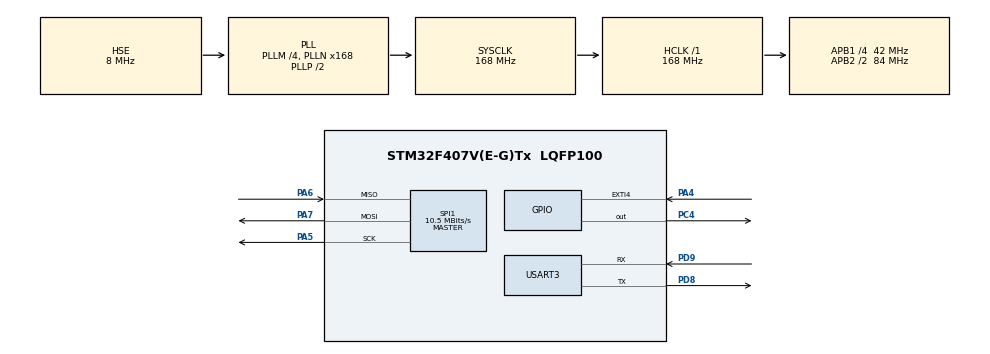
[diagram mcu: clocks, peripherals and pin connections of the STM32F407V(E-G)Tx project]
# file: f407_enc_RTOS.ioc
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Mcu.Family=STM32F4
RCC.PLLSourceVirtual=RCC_PLLSOURCE_HSE
NVIC.EXTI4_IRQn=true\:5\:0\:false\:false\:true\:true\:true\:true
PA6.Mode=Full_Duplex_Master
PH0-OSC_IN.Signal=RCC_OSC_IN
RCC.CortexFreq_Value=168000000
FREERTOS.Tasks01=defaultTask,0,128,StartDefaultTask,Default,NULL,Dynamic,NULL,NULL;Tcp,-3,128,Tcp_fn,Default,NULL,Dynamic,NULL,NULL
PA7.Mode=Full_Duplex_Master
SPI1.VirtualType=VM_MASTER
PC4.Signal=GPIO_Output
PD9.Signal=USART3_RX
RCC.APB1CLKDivider=RCC_HCLK_DIV4
PD9.Mode=Asynchronous
RCC.SYSCLKSource=RCC_SYSCLKSOURCE_PLLCLK
ProjectManager.StackSize=0x400
ProjectManager.TargetToolchain=TrueSTUDIO
SPI1.Direction=SPI_DIRECTION_2LINES
RCC.HCLKFreq_Value=168000000
RCC.APB2TimFreq_Value=168000000
TIM3.Period=999
SPI1.CalculateBaudRate=10.5 MBits/s
PD8.Signal=USART3_TX
TIM4.Prescaler=83
PD8.Mode=Asynchronous
RCC.AHBFreq_Value=168000000
PH0-OSC_IN.Mode=HSE-External-Oscillator
PA5.Signal=SPI1_SCK
RCC.HSE_VALUE=8000000
board=custom
RCC.VCOOutputFreq_Value=336000000
NVIC.TIM3_IRQn=true\:5\:0\:false\:false\:true\:true\:true\:true
RCC.APB2Freq_Value=84000000
SPI1.Mode=SPI_MODE_MASTER
TIM3.Prescaler=83
NVIC.TIM2_IRQn=true\:0\:0\:false\:false\:true\:false\:false\:true
PH1-OSC_OUT.Signal=RCC_OSC_OUT
TIM4.Period=999
VP_FREERTOS_VS_CMSIS_V1.Mode=CMSIS_V1
Mcu.Name=STM32F407V(E-G)Tx
FREERTOS.configTOTAL_HEAP_SIZE=51200
PH1-OSC_OUT.Mode=HSE-External-Oscillator
RCC.48MHZClocksFreq_Value=84000000
PA4.Signal=GPXTI4
RCC.SYSCLKFreq_VALUE=168000000
Mcu.Package=LQFP100
VP_SYS_VS_tim2.Mode=TIM2
PA6.Signal=SPI1_MISO
NVIC.TimeBase=TIM2_IRQn
USART3.VirtualMode=VM_ASYNC
NVIC.TimeBaseIP=TIM2
ProjectManager.HeapSize=0x200
RCC.HSI_VALUE=16000000
VP_TIM4_VS_ClockSourceINT.Mode=Internal
NVIC.PriorityGroup=NVIC_PRIORITYGROUP_4
RCC.APB2CLKDivider=RCC_HCLK_DIV2
RCC.PLLM=4
RCC.PLLN=168
RCC.APB1TimFreq_Value=84000000
NVIC.TIM4_IRQn=true\:5\:0\:false\:false\:true\:true\:true\:true
RCC.APB1Freq_Value=42000000
SPI1.BaudRatePrescaler=SPI_BAUDRATEPRESCALER_8
VP_TIM3_VS_ClockSourceINT.Mode=Internal
PA5.Mode=Full_Duplex_Master
PA7.Signal=SPI1_MOSI

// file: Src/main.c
/* USER CODE BEGIN Header */
/**
  ******************************************************************************
  * @file           : main.c
  * @brief          : Main program body
  ******************************************************************************
  * @attention
  *
  * <h2><center>&copy; Copyright (c) 2020 STMicroelectronics.
  * All rights reserved.</center></h2>
  *
  * This software component is licensed by ST under Ultimate Liberty license
  * SLA0044, the "License"; You may not use this file except in compliance with
  * the License. You may obtain a copy of the License at:
  *                             www.st.com/SLA0044
  *
  ******************************************************************************
  */
/* USER CODE END Header */

#include "main.h"
#include "cmsis_os.h"

/* USER CODE BEGIN Includes */
#include "lwip.h"
#include "ethernetif.h"
#include "app_ethernet.h"
#include "lwip/netif.h"
#include "lwip/tcpip.h"
#include "lwip/timeouts.h"
#include "lwip_mqtt.h"
#include "dht_22.h"

/* USER CODE END Includes */

SPI_HandleTypeDef hspi1;

TIM_HandleTypeDef htim3;
TIM_HandleTypeDef htim4;

UART_HandleTypeDef huart3;

osThreadId defaultTaskHandle;
osThreadId TcpHandle;
/* USER CODE BEGIN PV */
uint8_t Rh_byte1, Rh_byte2, Temp_byte1, Temp_byte2;
uint16_t sum, RH, TEMP;
int temp_low=0, temp_high=0, rh_low=0, rh_high=0;
GPIO_InitTypeDef GPIO_InitStruct;
/* USER CODE END PV */

void SystemClock_Config(void);
static void MX_GPIO_Init(void);
static void MX_SPI1_Init(void);
static void MX_TIM3_Init(void);
static void MX_TIM4_Init(void);
static void MX_USART3_UART_Init(void);
void StartDefaultTask(void const * argument);
void Tcp_fn(void const * argument);

/* USER CODE BEGIN PFP */
ip4_addr_t ipaddr;
ip4_addr_t netmask;
ip4_addr_t gw;
uint8_t IP_ADDRESS[4];
uint8_t NETMASK_ADDRESS[4];
uint8_t GATEWAY_ADDRESS[4];

/* USER CODE BEGIN 2 */
 struct netif gnetif; /* network interface structure */
 char pacote[1000];
 mqtt_client_t *client;
 uint32_t counter,tiner=0;
 struct netif gnetif; /* network interface structure */
 /* Semaphore to signal Ethernet Link state update */
 osSemaphoreId Netif_IRQSemaphore = NULL;
 /* Ethernet link thread Argument */
 struct enc_irq_str irq_arg;
/* USER CODE END PFP */

/* USER CODE BEGIN 0 */
 void MX_LWIP_Init(void);

#if (defined(__GNUC__) && !defined(__CC_ARM))
/* With GCC/RAISONANCE, small printf (option LD Linker->Libraries->Small printf
   set to 'Yes') calls __io_putchar() */
#define PUTCHAR_PROTOTYPE int __io_putchar(int ch)
#define GETCHAR_PROTOTYPE int __io_getchar(void)
#else
#define PUTCHAR_PROTOTYPE int fputc(int ch, FILE *f)
#define GETCHAR_PROTOTYPE int fgetc(FILE *f)
#endif /* __GNUC__ */

/**
  * @brief  Retargets the C library printf function to the USART.
  * @param  None
  * @retval None
  */
PUTCHAR_PROTOTYPE
{
  /* Place your implementation of fputc here */
  /* e.g. write a character to the USART2 and Loop until the end of transmission */
  while (HAL_OK != HAL_UART_Transmit(&huart3, (uint8_t *) &ch, 1, 30000))
  {
    ;
  }
  return ch;
}

/**
  * @brief  Retargets the C library scanf function to the USART.
  * @param  None
  * @retval None
  */
GETCHAR_PROTOTYPE
{
  /* Place your implementation of fgetc here */
  /* e.g. read a character on USART and loop until the end of read */
  uint8_t ch = 0;
  while (HAL_OK != HAL_UART_Receive(&huart3, (uint8_t *)&ch, 1, 30000))
  {
    ;
  }
  return ch;
}
/* USER CODE END 0 */

int main(void)
{

  /* MCU Configuration--------------------------------------------------------*/

  /* Reset of all peripherals, Initializes the Flash interface and the Systick. */
  HAL_Init();

  /* Configure the system clock */
  SystemClock_Config();

  /* Initialize all configured peripherals */
  MX_GPIO_Init();
  MX_SPI1_Init();
  MX_TIM3_Init();
  MX_TIM4_Init();
  MX_USART3_UART_Init();

  /* Create the thread(s) */
  /* definition and creation of defaultTask */

  /* Start scheduler */

  osThreadDef(defaultTask, StartDefaultTask, osPriorityNormal, 0, (9*1024));
  defaultTaskHandle = osThreadCreate(osThread(defaultTask), NULL);

  /* definition and creation of Tcp */
  osThreadDef(Tcp, Tcp_fn, osPriorityIdle, 0, 128);
  TcpHandle = osThreadCreate(osThread(Tcp), NULL);

  /* Start scheduler */
  osKernelStart();

  /* We should never get here as control is now taken by the scheduler */
  /* Infinite loop */
  while (1)
  {

  }
}

void SystemClock_Config(void)
{
  RCC_OscInitTypeDef RCC_OscInitStruct = {0};
  RCC_ClkInitTypeDef RCC_ClkInitStruct = {0};

  /** Configure the main internal regulator output voltage
  */
  __HAL_RCC_PWR_CLK_ENABLE();
  __HAL_PWR_VOLTAGESCALING_CONFIG(PWR_REGULATOR_VOLTAGE_SCALE1);
  /** Initializes the CPU, AHB and APB busses clocks
  */
  RCC_OscInitStruct.OscillatorType = RCC_OSCILLATORTYPE_HSE;
  RCC_OscInitStruct.HSEState = RCC_HSE_ON;
  RCC_OscInitStruct.PLL.PLLState = RCC_PLL_ON;
  RCC_OscInitStruct.PLL.PLLSource = RCC_PLLSOURCE_HSE;
  RCC_OscInitStruct.PLL.PLLM = 4;
  RCC_OscInitStruct.PLL.PLLN = 168;
  RCC_OscInitStruct.PLL.PLLP = RCC_PLLP_DIV2;
  RCC_OscInitStruct.PLL.PLLQ = 4;
  if (HAL_RCC_OscConfig(&RCC_OscInitStruct) != HAL_OK)
  {
    Error_Handler();
  }
  /** Initializes the CPU, AHB and APB busses clocks
  */
  RCC_ClkInitStruct.ClockType = RCC_CLOCKTYPE_HCLK|RCC_CLOCKTYPE_SYSCLK
                              |RCC_CLOCKTYPE_PCLK1|RCC_CLOCKTYPE_PCLK2;
  RCC_ClkInitStruct.SYSCLKSource = RCC_SYSCLKSOURCE_PLLCLK;
  RCC_ClkInitStruct.AHBCLKDivider = RCC_SYSCLK_DIV1;
  RCC_ClkInitStruct.APB1CLKDivider = RCC_HCLK_DIV4;
  RCC_ClkInitStruct.APB2CLKDivider = RCC_HCLK_DIV2;

  if (HAL_RCC_ClockConfig(&RCC_ClkInitStruct, FLASH_LATENCY_5) != HAL_OK)
  {
    Error_Handler();
  }
}

static void MX_SPI1_Init(void)
{

  /* SPI1 parameter configuration*/
  hspi1.Instance = SPI1;
  hspi1.Init.Mode = SPI_MODE_MASTER;
  hspi1.Init.Direction = SPI_DIRECTION_2LINES;
  hspi1.Init.DataSize = SPI_DATASIZE_8BIT;
  hspi1.Init.CLKPolarity = SPI_POLARITY_LOW;
  hspi1.Init.CLKPhase = SPI_PHASE_1EDGE;
  hspi1.Init.NSS = SPI_NSS_SOFT;
  hspi1.Init.BaudRatePrescaler = SPI_BAUDRATEPRESCALER_8;
  hspi1.Init.FirstBit = SPI_FIRSTBIT_MSB;
  hspi1.Init.TIMode = SPI_TIMODE_DISABLE;
  hspi1.Init.CRCCalculation = SPI_CRCCALCULATION_DISABLE;
  hspi1.Init.CRCPolynomial = 10;
  if (HAL_SPI_Init(&hspi1) != HAL_OK)
  {
    Error_Handler();
  }

}

static void MX_TIM3_Init(void)
{

  TIM_ClockConfigTypeDef sClockSourceConfig = {0};
  TIM_MasterConfigTypeDef sMasterConfig = {0};

  htim3.Instance = TIM3;
  htim3.Init.Prescaler = 83;
  htim3.Init.CounterMode = TIM_COUNTERMODE_UP;
  htim3.Init.Period = 999;
  htim3.Init.ClockDivision = TIM_CLOCKDIVISION_DIV1;
  htim3.Init.AutoReloadPreload = TIM_AUTORELOAD_PRELOAD_DISABLE;
  if (HAL_TIM_Base_Init(&htim3) != HAL_OK)
  {
    Error_Handler();
  }
  sClockSourceConfig.ClockSource = TIM_CLOCKSOURCE_INTERNAL;
  if (HAL_TIM_ConfigClockSource(&htim3, &sClockSourceConfig) != HAL_OK)
  {
    Error_Handler();
  }
  sMasterConfig.MasterOutputTrigger = TIM_TRGO_RESET;
  sMasterConfig.MasterSlaveMode = TIM_MASTERSLAVEMODE_DISABLE;
  if (HAL_TIMEx_MasterConfigSynchronization(&htim3, &sMasterConfig) != HAL_OK)
  {
    Error_Handler();
  }

}

static void MX_TIM4_Init(void)
{

  TIM_ClockConfigTypeDef sClockSourceConfig = {0};
  TIM_MasterConfigTypeDef sMasterConfig = {0};

  htim4.Instance = TIM4;
  htim4.Init.Prescaler = 83;
  htim4.Init.CounterMode = TIM_COUNTERMODE_UP;
  htim4.Init.Period = 9;
  htim4.Init.ClockDivision = TIM_CLOCKDIVISION_DIV1;
  htim4.Init.AutoReloadPreload = TIM_AUTORELOAD_PRELOAD_DISABLE;
  if (HAL_TIM_Base_Init(&htim4) != HAL_OK)
  {
    Error_Handler();
  }
  sClockSourceConfig.ClockSource = TIM_CLOCKSOURCE_INTERNAL;
  if (HAL_TIM_ConfigClockSource(&htim4, &sClockSourceConfig) != HAL_OK)
  {
    Error_Handler();
  }
  sMasterConfig.MasterOutputTrigger = TIM_TRGO_RESET;
  sMasterConfig.MasterSlaveMode = TIM_MASTERSLAVEMODE_DISABLE;
  if (HAL_TIMEx_MasterConfigSynchronization(&htim4, &sMasterConfig) != HAL_OK)
  {
    Error_Handler();
  }

}

static void MX_USART3_UART_Init(void)
{

  huart3.Instance = USART3;
  huart3.Init.BaudRate = 115200;
  huart3.Init.WordLength = UART_WORDLENGTH_8B;
  huart3.Init.StopBits = UART_STOPBITS_1;
  huart3.Init.Parity = UART_PARITY_NONE;
  huart3.Init.Mode = UART_MODE_TX_RX;
  huart3.Init.HwFlowCtl = UART_HWCONTROL_NONE;
  huart3.Init.OverSampling = UART_OVERSAMPLING_16;
  if (HAL_UART_Init(&huart3) != HAL_OK)
  {
    Error_Handler();
  }

}

static void MX_GPIO_Init(void)
{
  GPIO_InitTypeDef GPIO_InitStruct = {0};

  /* GPIO Ports Clock Enable */
  __HAL_RCC_GPIOH_CLK_ENABLE();
  __HAL_RCC_GPIOA_CLK_ENABLE();
  __HAL_RCC_GPIOC_CLK_ENABLE();
  __HAL_RCC_GPIOD_CLK_ENABLE();

  /*Configure GPIO pin Output Level */
  HAL_GPIO_WritePin(GPIOC, GPIO_PIN_4, GPIO_PIN_RESET);

  /*Configure GPIO pin : PA4 */
  GPIO_InitStruct.Pin = GPIO_PIN_4;
  GPIO_InitStruct.Mode = GPIO_MODE_IT_RISING;
  GPIO_InitStruct.Pull = GPIO_NOPULL;
  HAL_GPIO_Init(GPIOA, &GPIO_InitStruct);

  /*Configure GPIO pin : PC4 */
  GPIO_InitStruct.Pin = GPIO_PIN_4;
  GPIO_InitStruct.Mode = GPIO_MODE_OUTPUT_PP;
  GPIO_InitStruct.Pull = GPIO_NOPULL;
  GPIO_InitStruct.Speed = GPIO_SPEED_FREQ_LOW;
  HAL_GPIO_Init(GPIOC, &GPIO_InitStruct);

  HAL_GPIO_WritePin(GPIOC, DHT_22_PWR_Pin|DHT_22_GND_Pin, GPIO_PIN_RESET);
  /*Configure GPIO pins : DHT_22_PWR_Pin DHT_22_GND_Pin */
  GPIO_InitStruct.Pin = DHT_22_PWR_Pin|DHT_22_GND_Pin;
  GPIO_InitStruct.Mode = GPIO_MODE_OUTPUT_PP;
  GPIO_InitStruct.Pull = GPIO_NOPULL;
  GPIO_InitStruct.Speed = GPIO_SPEED_FREQ_LOW;
  HAL_GPIO_Init(GPIOC, &GPIO_InitStruct);

  /*Configure GPIO pin : DHT_22_IN_OUT_Pin */
  GPIO_InitStruct.Pin = DHT_22_IN_OUT_Pin;
  GPIO_InitStruct.Mode = GPIO_MODE_INPUT;
  GPIO_InitStruct.Pull = GPIO_NOPULL;
  HAL_GPIO_Init(DHT_22_IN_OUT_GPIO_Port, &GPIO_InitStruct);

  /* EXTI interrupt init*/
  HAL_NVIC_SetPriority(EXTI4_IRQn, 5, 0);
  HAL_NVIC_EnableIRQ(EXTI4_IRQn);

}

void StartDefaultTask(void const * argument)
{
  /* USER CODE BEGIN 5 */
	  MX_LWIP_Init();
	  User_notification(&gnetif);
	  client = mqtt_client_new();
	 if(client != NULL) {
	    sprintf(pacote,"hello_mohamed");
	     example_do_connect(client, "hello_world");
	     example_publish(client, pacote);
	 }
	   if(HAL_TIM_Base_Init(&htim3) != HAL_OK)
	   {
	     /* Initialization Error */
	     Error_Handler();
	   }

	   /*##-2- Start the TIM Base generation in interrupt mode ####################*/
	   /* Start Channel1 */
	   if(HAL_TIM_Base_Start_IT(&htim3) != HAL_OK)
	   {
	     /* Starting Error */
	     Error_Handler();
	   }
  /* Infinite loop */
  for(;;)
  {
ethernetif_input(&gnetif);
  /* Triggers actual ethernet transmission if transmission buffers are not empty */
 ethernet_transmit();
 osDelay(1);
 if(counter>399){
	   counter =0;
if(client != NULL) {
 tiner++;
 example_do_connect(client, "hello_world");
 sprintf(pacote,"hell timer:%d",tiner);
 example_publish(client, pacote);
  }
 }

  /* Handle timeouts */

  }
  /* USER CODE END 5 */
}

void Tcp_fn(void const * argument)
{
  /* USER CODE BEGIN Tcp_fn */
	HAL_GPIO_WritePin(DHT_22_GND_GPIO_Port,DHT_22_GND_Pin,GPIO_PIN_RESET);
		HAL_GPIO_WritePin(DHT_22_PWR_GPIO_Port,DHT_22_PWR_Pin,GPIO_PIN_SET);
		HAL_Delay(2000);
		  if(HAL_TIM_Base_Init(&htim4) != HAL_OK)
		  {
		    /* Initialization Error */
		    Error_Handler();
		  }
		  printf("here dht22_task\n\r");
  /* Infinite loop */
  for(;;)
{
printf("dht22_task loop \n\r");
DHT22_start ();
check_response ();
Rh_byte1 = read_data ();
Rh_byte2 = read_data ();
Temp_byte1 = read_data ();
Temp_byte2 = read_data ();
sum = read_data();
TEMP = ((Temp_byte1<<8)|Temp_byte2);
RH = ((Rh_byte1<<8)|Rh_byte2);
temp_low = TEMP/10;
temp_high = TEMP%10;
rh_low = RH/10;
rh_high = RH%10;
printf("\n\r********RH=%d.%d temp==%d.%d*********** \n\r",rh_low, rh_high,temp_low , temp_high);
  }
  /* USER CODE END Tcp_fn */
}

 /**
  * @brief  Period elapsed callback in non blocking mode
  * @note   This function is called  when TIM2 interrupt took place, inside
  * HAL_TIM_IRQHandler(). It makes a direct call to HAL_IncTick() to increment
  * a global variable "uwTick" used as application time base.
  * @param  htim : TIM handle
  * @retval None
  */
void HAL_TIM_PeriodElapsedCallback(TIM_HandleTypeDef *htim)
{
  if (htim->Instance == TIM2) {
    HAL_IncTick();
  }
  if (htim->Instance == TIM3) {
   counter++;

  }
}

void MX_LWIP_Init(void)
{
  /* IP addresses initialization */
  IP_ADDRESS[0] = 169;
  IP_ADDRESS[1] = 254;
  IP_ADDRESS[2] = 193;
  IP_ADDRESS[3] = 12;
  NETMASK_ADDRESS[0] = 255;
  NETMASK_ADDRESS[1] = 255;
  NETMASK_ADDRESS[2] = 0;
  NETMASK_ADDRESS[3] = 0;
  GATEWAY_ADDRESS[0] = 169;
  GATEWAY_ADDRESS[1] = 254;
  GATEWAY_ADDRESS[2] = 193;
  GATEWAY_ADDRESS[3] = 90;

  /* Initilialize the LwIP stack with RTOS */
  tcpip_init( NULL, NULL );

  IP4_ADDR(&ipaddr, IP_ADDR0, IP_ADDR1, IP_ADDR2, IP_ADDR3);
  IP4_ADDR(&netmask, NETMASK_ADDR0, NETMASK_ADDR1 , NETMASK_ADDR2, NETMASK_ADDR3);
  IP4_ADDR(&gw, GW_ADDR0, GW_ADDR1, GW_ADDR2, GW_ADDR3);
  /* create a binary semaphore used for informing ethernetif of frame reception */
  osSemaphoreDef(Netif_SEM);
  Netif_IRQSemaphore = osSemaphoreCreate(osSemaphore(Netif_SEM) , 1);

  /* add the network interface (IPv4/IPv6) with RTOS */
  netif_add(&gnetif, &ipaddr, &netmask, &gw, NULL, &ethernetif_init, &tcpip_input);

  /* Registers the default network interface */
  netif_set_default(&gnetif);

  if (netif_is_link_up(&gnetif))
  {
    /* When the netif is fully configured this function must be called */
    netif_set_up(&gnetif);
  }
  else
  {
    /* When the netif link is down this function must be called */
    netif_set_down(&gnetif);
  }
  netif_set_link_callback(&gnetif, ethernetif_update_config);

/* USER CODE BEGIN 3 */

	 //  irq_arg.netif = &gnetif;
	 //irq_arg.semaphore = Netif_IRQSemaphore;
  /* Create the Ethernet IRQ handler thread */
	 // osThreadDef(IrqThr, ethernetif_process_irq, osPriorityRealtime, 0, configMINIMAL_STACK_SIZE * 3);

	 // osThreadCreate (osThread(IrqThr), &irq_arg);
/* USER CODE END 3 */
}
void HAL_GPIO_EXTI_Callback(uint16_t GPIO_Pin)
{
//  /* Get the IT status register value */
//  if(BSP_IO_ITGetStatus(MII_INT_PIN))
  if (GPIO_Pin == ENC_INT_PIN)
  {
   ethernetif_set_link(&gnetif);
	 // ethernet_irq_handler(Netif_IRQSemaphore);

  }
  //BSP_IO_ITClear();
}

/**

void HAL_GPIO_EXTI_Callback(uint16_t GPIO_Pin)
{

  if (GPIO_Pin == ENC_INT_PIN)
  {
    ethernetif_set_link(&gnetif);
  }
}  */
void Error_Handler(void)
{
}

/************************ (C) COPYRIGHT STMicroelectronics *****END OF FILE****/
